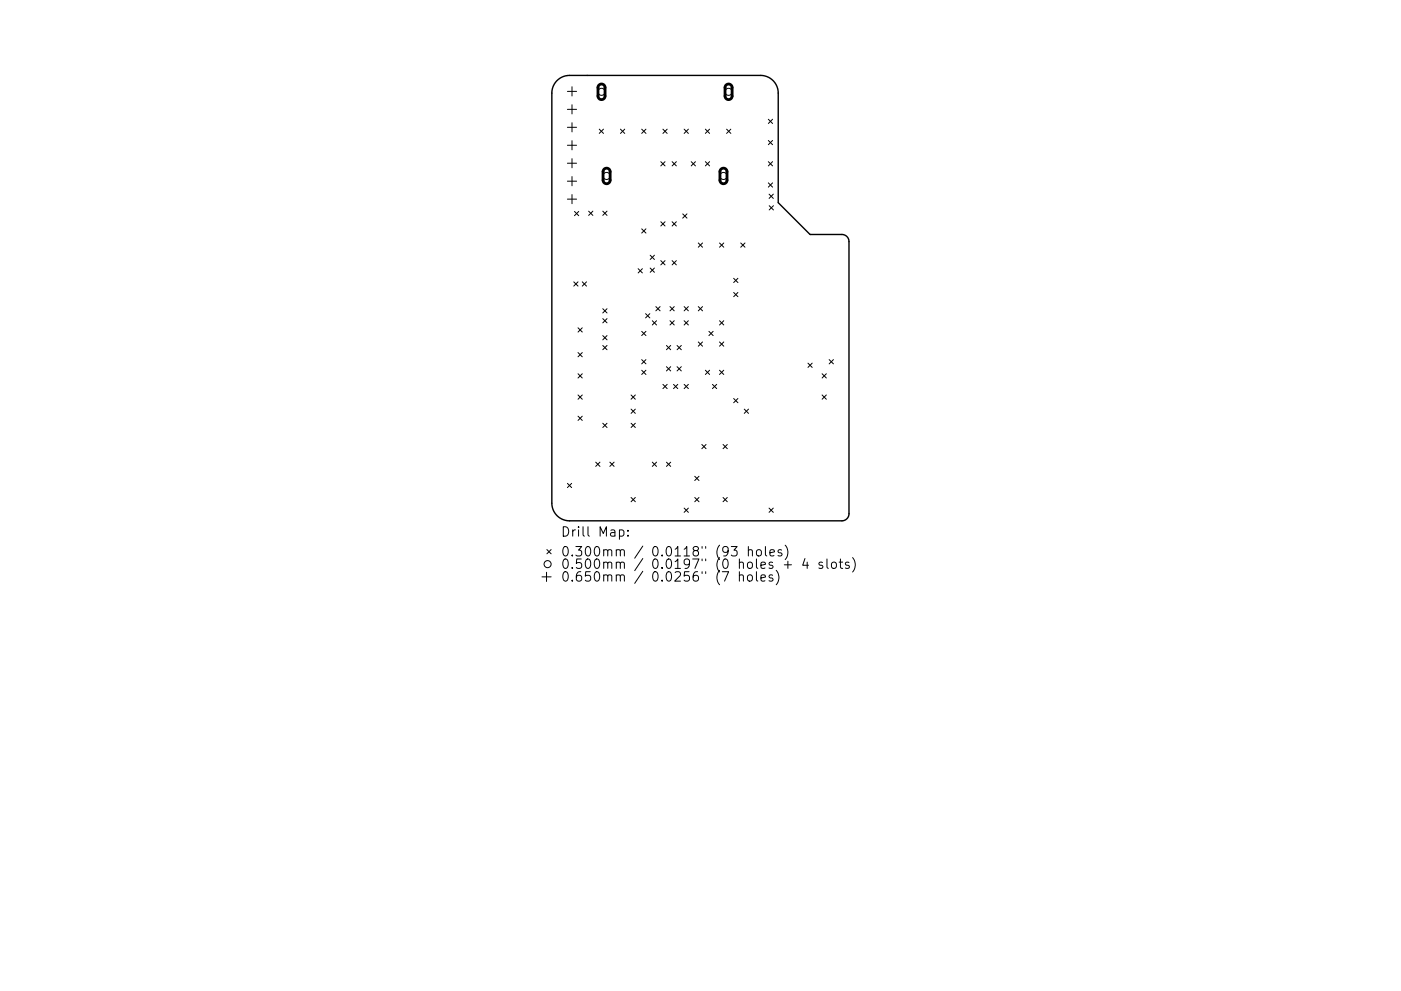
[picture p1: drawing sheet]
<svg xmlns="http://www.w3.org/2000/svg" width="297mm" height="210mm" viewBox="0 0 297 210" stroke-linecap="round" stroke-linejoin="round" font-family="sans-serif">
<defs><g id="words">
<g font-size="2.8">
<text x="118.9" y="113.9">Drill Map:</text>
<text x="118.9" y="118.1">0.300mm / 0.0118&quot; (93 holes)</text>
<text x="118.9" y="120.7">0.500mm / 0.0197&quot; (0 holes + 4 slots)</text>
<text x="118.9" y="123.4">0.650mm / 0.0256&quot; (7 holes)</text>
</g>
</g></defs>
<path d="M118.1 17.1a3.8 3.8 0 0 1 2.7-1.1h40.5a3.8 3.8 0 0 1 3.7 3.8v23.2l6.8 6.8h6.7a1.5 1.5 0 0 1 1.5 1.5v57.7a1.5 1.5 0 0 1-1.5 1.5h-57.7a3.8 3.8 0 0 1-3.8-3.7v-87a3.8 3.8 0 0 1 1.1-2.7z" fill="none" stroke="#000" stroke-width=".3"/>
<g fill="none" stroke="#000" stroke-width=".21">
<path d="M120.3 19.4h2M121.3 18.4v2M120.3 23.2h2M120.3 27h2M120.3 30.8h2M120.3 34.6h2M120.3 38.4h2M121.3 22.2v2M121.3 26v2M121.3 29.8v2M121.3 33.7v1.9M121.3 37.5v1.9"/>
<path d="M127.1 27.4l.9 .9M128 27.4l-.9 .9M131.6 27.4l.9 .9M132.5 27.4l-.9 .9M136.1 27.4l.9 .9M137 27.4l-.9 .9M140.1 34.3l.9 .9M140.6 27.4l.9 .9M141 34.3l-.9 .9M141.5 27.4l-.9 .9M142.5 34.3l.9 .9M143.4 34.3l-.9 .9"/>
<path d="M145.1 27.4l.9 .9M146 27.4l-.9 .9M146.6 34.3l.9 .9M147.5 34.3l-.9 .9M149.5 27.4l.9 .9M149.6 34.3l.9 .9M150.4 27.4l-.9 .9M150.5 34.3l-.9 .9M154.1 27.4l.9 .9M155 27.4l-.9 .9M162.9 25.3l.9 .9M162.9 29.8l.9 .9"/>
<path d="M162.9 34.3l.9 .9M162.9 38.8l.9 .9M163.8 25.3l-.9 .9M163.8 29.8l-.9 .9M163.8 34.3l-.9 .9M163.8 38.8l-.9 .9M120.3 42.3h2M121.3 41.3v1.9M121.7 59.8l.9 .9M121.8 44.9l.9 .9M122.6 59.8l-.9 .9M122.7 44.9l-.9 .9"/>
<path d="M123.5 59.8l.9 .9M124.4 59.8l-.9 .9M124.8 44.8l.9 .9M125.7 44.8l-.9 .9M127.8 44.8l.9 .9M128.7 44.8l-.9 .9M135.3 57l.9 .9M136.1 48.6l.9 .9M136.2 57l-.9 .9M137 48.6l-.9 .9M137.9 54.1l.9 .9M137.9 56.9l.9 .9"/>
<path d="M138.8 54.1l-.9 .9M138.8 56.9l-.9 .9M140.1 47.1l.9 .9M140.1 55.3l.9 .9M141 55.3l-.9 .9M141 47.1l-.9 .9M142.5 47.1l.9 .9M142.5 55.3l.9 .9M143.4 47.1l-.9 .9M143.4 55.3l-.9 .9M144.7 45.4l.9 .9M145.6 45.4l-.9 .9"/>
<path d="M148.1 51.6l.9 .9M149 51.6l-.9 .9M152.6 51.6l.9 .9M153.5 51.6l-.9 .9M155.6 59.1l.9 .9M156.5 59.1l-.9 .9M157.1 51.6l.9 .9M158 51.6l-.9 .9M163.1 41.2l.9 .9M163.1 43.6l.9 .9M164 41.2l-.9 .9M164 43.6l-.9 .9"/>
<path d="M122.6 69.6l.9 .9M122.6 74.8l.9 .9M122.6 79.3l.9 .9M123.5 69.6l-.9 .9M123.5 74.8l-.9 .9M123.5 79.3l-.9 .9M127.8 65.5l.9 .9M127.8 67.6l.9 .9M127.8 71.2l.9 .9M127.8 73.3l.9 .9M128.7 65.5l-.9 .9M128.7 67.6l-.9 .9"/>
<path d="M128.7 71.2l-.9 .9M128.7 73.3l-.9 .9M136.1 70.3l.9 .9M136.1 76.3l.9 .9M136.1 78.6l.9 .9M136.9 66.6l.9 .9M137 70.3l-.9 .9M137 76.3l-.9 .9M137 78.6l-.9 .9M137.8 66.6l-.9 .9M138.3 68.1l.9 .9M139.1 65.1l.9 .9"/>
<path d="M139.2 68.1l-.9 .9M140 65.1l-.9 .9M141.3 73.3l.9 .9M141.3 77.8l.9 .9M142.1 65.1l.9 .9M142.1 68.1l.9 .9M142.2 73.3l-.9 .9M142.2 77.8l-.9 .9M143 65.1l-.9 .9M143 68.1l-.9 .9M143.6 77.8l.9 .9M143.6 73.3l.9 .9"/>
<path d="M144.5 73.3l-.9 .9M144.5 77.8l-.9 .9M145.1 68.1l.9 .9M145.1 65.1l.9 .9M146 65.1l-.9 .9M146 68.1l-.9 .9M148.1 65.1l.9 .9M148.1 72.6l.9 .9M149 72.6l-.9 .9M149 65.1l-.9 .9M149.6 78.6l.9 .9M150.3 70.3l.9 .9"/>
<path d="M150.5 78.6l-.9 .9M151.2 70.3l-.9 .9M152.6 78.6l.9 .9M152.6 72.6l.9 .9M152.6 68.1l.9 .9M153.5 68.1l-.9 .9M153.5 72.6l-.9 .9M153.5 78.6l-.9 .9M155.6 62.1l.9 .9M156.5 62.1l-.9 .9M171.3 77.1l.9 .9M172.2 77.1l-.9 .9"/>
<path d="M174.3 79.3l.9 .9M175.2 79.3l-.9 .9M175.8 76.3l.9 .9M176.7 76.3l-.9 .9M122.6 83.8l.9 .9M122.6 88.3l.9 .9M123.5 83.8l-.9 .9M123.5 88.3l-.9 .9M126.3 98.1l.9 .9M127.2 98.1l-.9 .9M127.8 89.8l.9 .9M128.7 89.8l-.9 .9"/>
<path d="M129.3 98.1l.9 .9M130.2 98.1l-.9 .9M133.8 83.8l.9 .9M133.8 86.8l.9 .9M133.8 89.8l.9 .9M134.7 83.8l-.9 .9M134.7 86.8l-.9 .9M134.7 89.8l-.9 .9M138.3 98.1l.9 .9M139.2 98.1l-.9 .9M140.6 81.6l.9 .9M141.3 98.1l.9 .9"/>
<path d="M141.5 81.6l-.9 .9M142.2 98.1l-.9 .9M142.8 81.6l.9 .9M143.7 81.6l-.9 .9M145.1 81.6l.9 .9M146 81.6l-.9 .9M148.8 94.3l.9 .9M149.7 94.3l-.9 .9M151.1 81.6l.9 .9M152 81.6l-.9 .9M153.3 94.3l.9 .9M154.2 94.3l-.9 .9"/>
<path d="M155.6 84.6l.9 .9M156.5 84.6l-.9 .9M157.8 86.8l.9 .9M158.7 86.8l-.9 .9M174.3 83.8l.9 .9M175.2 83.8l-.9 .9M116 116.6l.9 .9M116.9 116.6l-.9 .9M120.3 102.6l.9 .9M121.2 102.6l-.9 .9M131.3 112.5l.6-.1 .4 .4v.6l-.2 .3h-.8M133.1 113.6v.2"/>
<path d="M133.1 112.5v.2M133.8 105.6l.9 .9M134.7 105.6l-.9 .9M145.1 107.8l.9 .9M146 107.8l-.9 .9M147.3 101.1l.9 .9M147.3 105.6l.9 .9M148.2 105.6l-.9 .9M148.2 101.1l-.9 .9M153.3 105.6l.9 .9M154.2 105.6l-.9 .9M155 116h1.3l-.7 .7a.54 .54 0 0 1 .7 .4v.5l-.2 .3-.8 .1-.3-.2"/>
<path d="M158.7 116.8a.5 .5 0 0 1 .8 .1v1.1M158.7 116v2M160.5 116.8a.54 .54 0 0 1 .5-.2 .54 .54 0 0 1 .4 .4v.6a.54 .54 0 0 1-.5 .4 .54 .54 0 0 1-.5-.4zM162.3 116v1.7l.3 .3M163.1 107.8l.9 .9M163.2 117.3l1-.2-.1-.4-.6-.1-.3 .3 .1 1h.8M164 107.8l-.9 .9M165.7 116.7l-.5-.1-.2 .3v.3l.7 .2v.5h-.7M166.3 119.8h1.5M166.5 115.7a2.29 2.29 0 0 1 0 3M167 119.1v1.5M170.7 118.5l-.5 1.4h1.2"/>
<path d="M171.1 119.3v1.3M174.4 119.4l-.5-.1-.3 .2 .1 .3 .7 .2v.5h-.8M175.3 118.6v1.7l.3 .3M176.4 119.5a.54 .54 0 0 1 .5-.2 .54 .54 0 0 1 .4 .3v.6a.54 .54 0 0 1-.5 .4 .54 .54 0 0 1-.5-.4zM177.9 119.3h.8M178.2 118.6v1.7l.1 .2 .4 .1M180 119.4l-.5-.1-.3 .2 .1 .3 .7 .2v.5h-.8M180.8 118.3a2.29 2.29 0 0 1 0 3.1M114.9 122.4h2M115.9 121.4v2M156.8 122.2a.5 .5 0 0 1 .8 0v1.1M156.8 121.3v2"/>
<path d="M158.6 122.2a.54 .54 0 0 1 .5-.2 .54 .54 0 0 1 .4 .3v.6a.54 .54 0 0 1-.5 .4 .54 .54 0 0 1-.5-.4zM160.4 121.3v1.7l.3 .3M161.3 122.6l1-.2-.1-.3-.6-.1-.3 .2 .1 1h.8M163.8 122.1l-.5-.1-.3 .2 .1 .3 .7 .2v.5h-.8M164.6 121a2.29 2.29 0 0 1 0 3.1"/>
<circle cx="127.5" cy="19.5" r=".75"/>
<circle cx="154.5" cy="19.5" r=".75"/>
<circle cx="128.6" cy="37.3" r=".75"/>
<circle cx="153.4" cy="37.3" r=".75"/>
<circle cx="116.1" cy="119.7" r=".75"/>
</g>
<path d="M127 18.1a.75 .75 0 0 1 .8-.2 .75 .75 0 0 1 .5 .7v1.8a.75 .75 0 0 1-.8 .7 .75 .75 0 0 1-.7-.7v-1.9zM153.9 18.1a.75 .75 0 0 1 .9-.2 .75 .75 0 0 1 .4 .7v1.8a.75 .75 0 0 1-.7 .7 .75 .75 0 0 1-.8-.7v-1.9zM128.1 35.9a.75 .75 0 0 1 .8-.2 .75 .75 0 0 1 .5 .7v1.8a.75 .75 0 0 1-.8 .8 .75 .75 0 0 1-.7-.8v-1.8zM152.9 35.9a.75 .75 0 0 1 .8-.2 .75 .75 0 0 1 .4 .7v1.8a.75 .75 0 0 1-.7 .8 .75 .75 0 0 1-.8-.8v-1.8z" fill="none" stroke="#000" stroke-width=".6"/>
<use href="#words"/>
</svg>
